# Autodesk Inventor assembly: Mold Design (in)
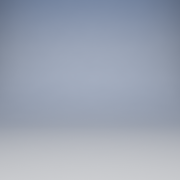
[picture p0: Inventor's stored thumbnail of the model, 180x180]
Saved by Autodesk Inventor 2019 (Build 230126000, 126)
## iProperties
Shininess: 64.0
Length Units: 11272
Angle Units: 11279
Time Units: 11290
Mass Units: 11286
Length Display Precision: 3
Angle Display Precision: 2
Compacted: True
Part Number: Mold Design (in)
Document SubType Name: Assembly
Created: 2002-07
Material: Všeobecné
Density: 0.0
Volumn: 0.0
Area: 0.0
PropertySet Name: Model Information
Control State: 0
Master: False
Checked Out: False
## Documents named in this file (1)
- C:\Users\CSY\Desktop\csy-126\English.Base\Mold Design (in).iam
